VERSION 5.7 ;
  NOWIREEXTENSIONATPIN ON ;
  DIVIDERCHAR "/" ;
  BUSBITCHARS "[]" ;
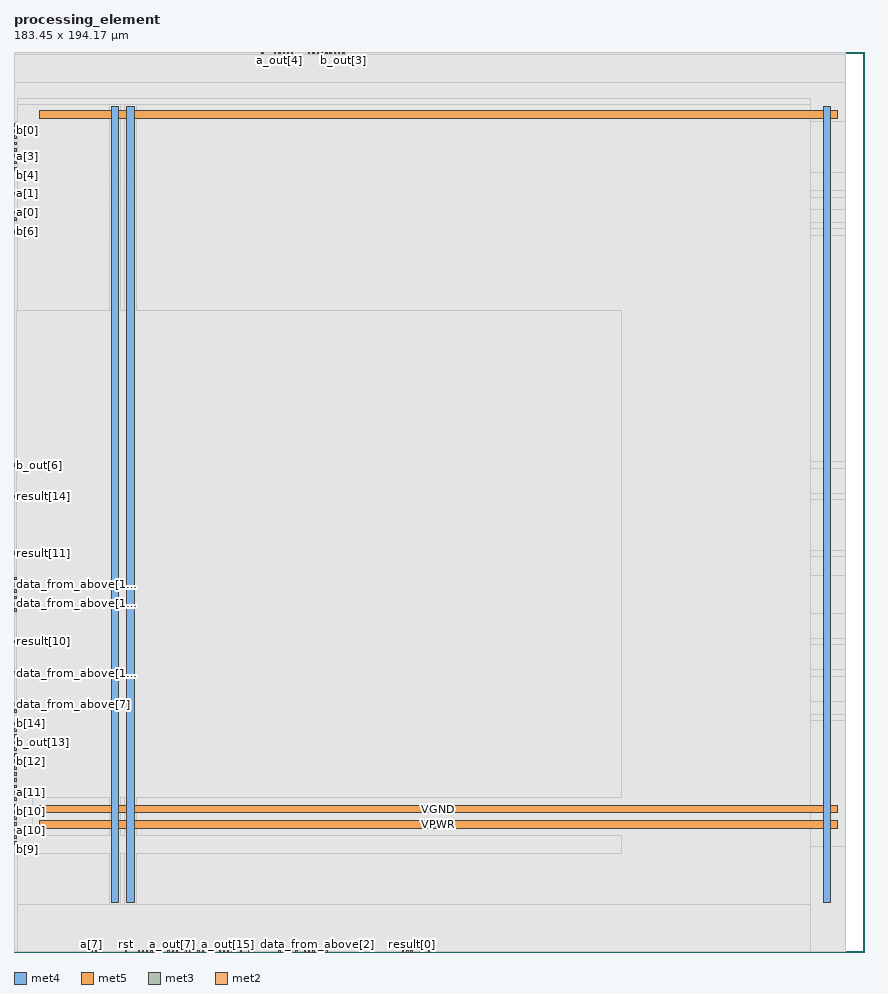
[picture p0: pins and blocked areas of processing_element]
MACRO processing_element
  CLASS BLOCK ;
  FOREIGN processing_element ;
  ORIGIN 0.000 0.000 ;
  SIZE 183.450 BY 194.170 ;
  PIN VGND
    DIRECTION INOUT ;
    USE GROUND ;
    PORT
      LAYER met4 ;
        RECT 24.340 10.640 25.940 182.480 ;
    END
    PORT
      LAYER met5 ;
        RECT 5.520 30.030 177.560 31.630 ;
    END
  END VGND
  PIN VPWR
    DIRECTION INOUT ;
    USE POWER ;
    PORT
      LAYER met4 ;
        RECT 21.040 10.640 22.640 182.480 ;
    END
    PORT
      LAYER met4 ;
        RECT 174.640 10.640 176.240 182.480 ;
    END
    PORT
      LAYER met5 ;
        RECT 5.520 26.730 177.560 28.330 ;
    END
    PORT
      LAYER met5 ;
        RECT 5.520 179.910 177.560 181.510 ;
    END
  END VPWR
  PIN a[0]
    DIRECTION INPUT ;
    USE SIGNAL ;
    ANTENNAGATEAREA 0.196500 ;
    PORT
      LAYER met3 ;
        RECT 0.000 159.160 0.600 159.760 ;
    END
  END a[0]
  PIN a[10]
    DIRECTION INPUT ;
    USE SIGNAL ;
    ANTENNAGATEAREA 0.631200 ;
    ANTENNADIFFAREA 0.434700 ;
    PORT
      LAYER met3 ;
        RECT 0.000 27.240 0.600 27.840 ;
    END
  END a[10]
  PIN a[11]
    DIRECTION INPUT ;
    USE SIGNAL ;
    ANTENNAGATEAREA 0.196500 ;
    PORT
      LAYER met3 ;
        RECT 0.000 34.040 0.600 34.640 ;
    END
  END a[11]
  PIN a[12]
    DIRECTION INPUT ;
    USE SIGNAL ;
    ANTENNAGATEAREA 0.196500 ;
    PORT
      LAYER met3 ;
        RECT 0.000 36.760 0.600 37.360 ;
    END
  END a[12]
  PIN a[13]
    DIRECTION INPUT ;
    USE SIGNAL ;
    ANTENNAGATEAREA 0.196500 ;
    PORT
      LAYER met3 ;
        RECT 0.000 46.280 0.600 46.880 ;
    END
  END a[13]
  PIN a[14]
    DIRECTION INPUT ;
    USE SIGNAL ;
    ANTENNAGATEAREA 0.196500 ;
    PORT
      LAYER met3 ;
        RECT 0.000 35.400 0.600 36.000 ;
    END
  END a[14]
  PIN a[15]
    DIRECTION INPUT ;
    USE SIGNAL ;
    ANTENNAGATEAREA 0.631200 ;
    ANTENNADIFFAREA 0.434700 ;
    PORT
      LAYER met2 ;
        RECT 38.730 0.000 39.010 0.280 ;
    END
  END a[15]
  PIN a[1]
    DIRECTION INPUT ;
    USE SIGNAL ;
    ANTENNAGATEAREA 0.196500 ;
    PORT
      LAYER met3 ;
        RECT 0.000 163.240 0.600 163.840 ;
    END
  END a[1]
  PIN a[2]
    DIRECTION INPUT ;
    USE SIGNAL ;
    ANTENNAGATEAREA 0.196500 ;
    PORT
      LAYER met2 ;
        RECT 59.890 193.890 60.170 194.170 ;
    END
  END a[2]
  PIN a[3]
    DIRECTION INPUT ;
    USE SIGNAL ;
    ANTENNAGATEAREA 0.196500 ;
    PORT
      LAYER met3 ;
        RECT 0.000 171.400 0.600 172.000 ;
    END
  END a[3]
  PIN a[4]
    DIRECTION INPUT ;
    USE SIGNAL ;
    ANTENNAGATEAREA 0.196500 ;
    PORT
      LAYER met3 ;
        RECT 0.000 175.480 0.600 176.080 ;
    END
  END a[4]
  PIN a[5]
    DIRECTION INPUT ;
    USE SIGNAL ;
    ANTENNAGATEAREA 0.196500 ;
    PORT
      LAYER met3 ;
        RECT 0.000 170.040 0.600 170.640 ;
    END
  END a[5]
  PIN a[6]
    DIRECTION INPUT ;
    USE SIGNAL ;
    ANTENNAGATEAREA 0.631200 ;
    ANTENNADIFFAREA 0.434700 ;
    PORT
      LAYER met3 ;
        RECT 0.000 178.200 0.600 178.800 ;
    END
  END a[6]
  PIN a[7]
    DIRECTION INPUT ;
    USE SIGNAL ;
    ANTENNAGATEAREA 0.631200 ;
    ANTENNADIFFAREA 0.434700 ;
    PORT
      LAYER met2 ;
        RECT 16.650 0.000 16.930 0.280 ;
    END
  END a[7]
  PIN a[8]
    DIRECTION INPUT ;
    USE SIGNAL ;
    ANTENNAGATEAREA 0.196500 ;
    PORT
      LAYER met2 ;
        RECT 18.490 0.000 18.770 0.280 ;
    END
  END a[8]
  PIN a[9]
    DIRECTION INPUT ;
    USE SIGNAL ;
    ANTENNAGATEAREA 0.631200 ;
    ANTENNADIFFAREA 0.434700 ;
    PORT
      LAYER met3 ;
        RECT 0.000 24.520 0.600 25.120 ;
    END
  END a[9]
  PIN a_out[0]
    DIRECTION OUTPUT ;
    USE SIGNAL ;
    ANTENNADIFFAREA 0.795200 ;
    PORT
      LAYER met2 ;
        RECT 66.330 193.890 66.610 194.170 ;
    END
  END a_out[0]
  PIN a_out[10]
    DIRECTION OUTPUT ;
    USE SIGNAL ;
    ANTENNADIFFAREA 0.795200 ;
    PORT
      LAYER met2 ;
        RECT 37.810 0.000 38.090 0.280 ;
    END
  END a_out[10]
  PIN a_out[11]
    DIRECTION OUTPUT ;
    USE SIGNAL ;
    ANTENNADIFFAREA 0.795200 ;
    PORT
      LAYER met2 ;
        RECT 40.570 0.000 40.850 0.280 ;
    END
  END a_out[11]
  PIN a_out[12]
    DIRECTION OUTPUT ;
    USE SIGNAL ;
    ANTENNADIFFAREA 0.795200 ;
    PORT
      LAYER met3 ;
        RECT 0.000 38.120 0.600 38.720 ;
    END
  END a_out[12]
  PIN a_out[13]
    DIRECTION OUTPUT ;
    USE SIGNAL ;
    ANTENNADIFFAREA 0.795200 ;
    PORT
      LAYER met2 ;
        RECT 35.050 0.000 35.330 0.280 ;
    END
  END a_out[13]
  PIN a_out[14]
    DIRECTION OUTPUT ;
    USE SIGNAL ;
    ANTENNADIFFAREA 0.795200 ;
    PORT
      LAYER met2 ;
        RECT 35.970 0.000 36.250 0.280 ;
    END
  END a_out[14]
  PIN a_out[15]
    DIRECTION OUTPUT ;
    USE SIGNAL ;
    ANTENNADIFFAREA 0.795200 ;
    PORT
      LAYER met2 ;
        RECT 46.090 0.000 46.370 0.280 ;
    END
  END a_out[15]
  PIN a_out[1]
    DIRECTION OUTPUT ;
    USE SIGNAL ;
    ANTENNADIFFAREA 0.795200 ;
    PORT
      LAYER met2 ;
        RECT 67.250 193.890 67.530 194.170 ;
    END
  END a_out[1]
  PIN a_out[2]
    DIRECTION OUTPUT ;
    USE SIGNAL ;
    ANTENNADIFFAREA 0.795200 ;
    PORT
      LAYER met2 ;
        RECT 70.010 193.890 70.290 194.170 ;
    END
  END a_out[2]
  PIN a_out[3]
    DIRECTION OUTPUT ;
    USE SIGNAL ;
    ANTENNADIFFAREA 0.795200 ;
    PORT
      LAYER met2 ;
        RECT 63.570 193.890 63.850 194.170 ;
    END
  END a_out[3]
  PIN a_out[4]
    DIRECTION OUTPUT ;
    USE SIGNAL ;
    ANTENNADIFFAREA 0.795200 ;
    PORT
      LAYER met2 ;
        RECT 57.130 193.890 57.410 194.170 ;
    END
  END a_out[4]
  PIN a_out[5]
    DIRECTION OUTPUT ;
    USE SIGNAL ;
    ANTENNADIFFAREA 0.795200 ;
    PORT
      LAYER met2 ;
        RECT 58.050 193.890 58.330 194.170 ;
    END
  END a_out[5]
  PIN a_out[6]
    DIRECTION OUTPUT ;
    USE SIGNAL ;
    ANTENNADIFFAREA 0.795200 ;
    PORT
      LAYER met2 ;
        RECT 53.450 193.890 53.730 194.170 ;
    END
  END a_out[6]
  PIN a_out[7]
    DIRECTION OUTPUT ;
    USE SIGNAL ;
    ANTENNADIFFAREA 0.795200 ;
    PORT
      LAYER met2 ;
        RECT 34.130 0.000 34.410 0.280 ;
    END
  END a_out[7]
  PIN a_out[8]
    DIRECTION OUTPUT ;
    USE SIGNAL ;
    ANTENNADIFFAREA 0.795200 ;
    PORT
      LAYER met2 ;
        RECT 33.210 0.000 33.490 0.280 ;
    END
  END a_out[8]
  PIN a_out[9]
    DIRECTION OUTPUT ;
    USE SIGNAL ;
    ANTENNADIFFAREA 0.795200 ;
    PORT
      LAYER met2 ;
        RECT 36.890 0.000 37.170 0.280 ;
    END
  END a_out[9]
  PIN b[0]
    DIRECTION INPUT ;
    USE SIGNAL ;
    ANTENNAGATEAREA 0.196500 ;
    PORT
      LAYER met3 ;
        RECT 0.000 176.840 0.600 177.440 ;
    END
  END b[0]
  PIN b[10]
    DIRECTION INPUT ;
    USE SIGNAL ;
    ANTENNAGATEAREA 0.631200 ;
    ANTENNADIFFAREA 0.434700 ;
    PORT
      LAYER met3 ;
        RECT 0.000 29.960 0.600 30.560 ;
    END
  END b[10]
  PIN b[11]
    DIRECTION INPUT ;
    USE SIGNAL ;
    ANTENNAGATEAREA 0.631200 ;
    ANTENNADIFFAREA 0.434700 ;
    PORT
      LAYER met3 ;
        RECT 0.000 32.680 0.600 33.280 ;
    END
  END b[11]
  PIN b[12]
    DIRECTION INPUT ;
    USE SIGNAL ;
    ANTENNAGATEAREA 0.196500 ;
    PORT
      LAYER met3 ;
        RECT 0.000 40.840 0.600 41.440 ;
    END
  END b[12]
  PIN b[13]
    DIRECTION INPUT ;
    USE SIGNAL ;
    ANTENNAGATEAREA 0.196500 ;
    PORT
      LAYER met3 ;
        RECT 0.000 42.200 0.600 42.800 ;
    END
  END b[13]
  PIN b[14]
    DIRECTION INPUT ;
    USE SIGNAL ;
    ANTENNAGATEAREA 0.631200 ;
    ANTENNADIFFAREA 0.434700 ;
    PORT
      LAYER met3 ;
        RECT 0.000 47.640 0.600 48.240 ;
    END
  END b[14]
  PIN b[15]
    DIRECTION INPUT ;
    USE SIGNAL ;
    ANTENNAGATEAREA 0.196500 ;
    PORT
      LAYER met2 ;
        RECT 39.650 0.000 39.930 0.280 ;
    END
  END b[15]
  PIN b[1]
    DIRECTION INPUT ;
    USE SIGNAL ;
    ANTENNAGATEAREA 0.196500 ;
    PORT
      LAYER met2 ;
        RECT 56.210 193.890 56.490 194.170 ;
    END
  END b[1]
  PIN b[2]
    DIRECTION INPUT ;
    USE SIGNAL ;
    ANTENNAGATEAREA 0.196500 ;
    PORT
      LAYER met3 ;
        RECT 0.000 174.120 0.600 174.720 ;
    END
  END b[2]
  PIN b[3]
    DIRECTION INPUT ;
    USE SIGNAL ;
    ANTENNAGATEAREA 0.196500 ;
    PORT
      LAYER met3 ;
        RECT 0.000 172.760 0.600 173.360 ;
    END
  END b[3]
  PIN b[4]
    DIRECTION INPUT ;
    USE SIGNAL ;
    ANTENNAGATEAREA 0.631200 ;
    ANTENNADIFFAREA 0.434700 ;
    PORT
      LAYER met3 ;
        RECT 0.000 168.680 0.600 169.280 ;
    END
  END b[4]
  PIN b[5]
    DIRECTION INPUT ;
    USE SIGNAL ;
    ANTENNAGATEAREA 0.196500 ;
    PORT
      LAYER met3 ;
        RECT 0.000 157.800 0.600 158.400 ;
    END
  END b[5]
  PIN b[6]
    DIRECTION INPUT ;
    USE SIGNAL ;
    ANTENNAGATEAREA 0.196500 ;
    PORT
      LAYER met3 ;
        RECT 0.000 155.080 0.600 155.680 ;
    END
  END b[6]
  PIN b[7]
    DIRECTION INPUT ;
    USE SIGNAL ;
    ANTENNAGATEAREA 0.631200 ;
    ANTENNADIFFAREA 0.434700 ;
    PORT
      LAYER met3 ;
        RECT 0.000 28.600 0.600 29.200 ;
    END
  END b[7]
  PIN b[8]
    DIRECTION INPUT ;
    USE SIGNAL ;
    ANTENNAGATEAREA 0.631200 ;
    ANTENNADIFFAREA 0.434700 ;
    PORT
      LAYER met3 ;
        RECT 0.000 25.880 0.600 26.480 ;
    END
  END b[8]
  PIN b[9]
    DIRECTION INPUT ;
    USE SIGNAL ;
    ANTENNAGATEAREA 0.196500 ;
    PORT
      LAYER met3 ;
        RECT 0.000 23.160 0.600 23.760 ;
    END
  END b[9]
  PIN b_out[0]
    DIRECTION OUTPUT ;
    USE SIGNAL ;
    ANTENNADIFFAREA 0.795200 ;
    PORT
      LAYER met2 ;
        RECT 58.970 193.890 59.250 194.170 ;
    END
  END b_out[0]
  PIN b_out[10]
    DIRECTION OUTPUT ;
    USE SIGNAL ;
    ANTENNADIFFAREA 0.795200 ;
    PORT
      LAYER met2 ;
        RECT 26.770 0.000 27.050 0.280 ;
    END
  END b_out[10]
  PIN b_out[11]
    DIRECTION OUTPUT ;
    USE SIGNAL ;
    ANTENNADIFFAREA 0.795200 ;
    PORT
      LAYER met3 ;
        RECT 0.000 31.320 0.600 31.920 ;
    END
  END b_out[11]
  PIN b_out[12]
    DIRECTION OUTPUT ;
    USE SIGNAL ;
    ANTENNADIFFAREA 0.795200 ;
    PORT
      LAYER met3 ;
        RECT 0.000 39.480 0.600 40.080 ;
    END
  END b_out[12]
  PIN b_out[13]
    DIRECTION OUTPUT ;
    USE SIGNAL ;
    ANTENNADIFFAREA 0.795200 ;
    PORT
      LAYER met3 ;
        RECT 0.000 43.560 0.600 44.160 ;
    END
  END b_out[13]
  PIN b_out[14]
    DIRECTION OUTPUT ;
    USE SIGNAL ;
    ANTENNADIFFAREA 0.795200 ;
    PORT
      LAYER met3 ;
        RECT 0.000 49.000 0.600 49.600 ;
    END
  END b_out[14]
  PIN b_out[15]
    DIRECTION OUTPUT ;
    USE SIGNAL ;
    ANTENNADIFFAREA 0.795200 ;
    PORT
      LAYER met2 ;
        RECT 47.010 0.000 47.290 0.280 ;
    END
  END b_out[15]
  PIN b_out[1]
    DIRECTION OUTPUT ;
    USE SIGNAL ;
    ANTENNADIFFAREA 0.795200 ;
    PORT
      LAYER met2 ;
        RECT 65.410 193.890 65.690 194.170 ;
    END
  END b_out[1]
  PIN b_out[2]
    DIRECTION OUTPUT ;
    USE SIGNAL ;
    ANTENNADIFFAREA 0.795200 ;
    PORT
      LAYER met2 ;
        RECT 68.170 193.890 68.450 194.170 ;
    END
  END b_out[2]
  PIN b_out[3]
    DIRECTION OUTPUT ;
    USE SIGNAL ;
    ANTENNADIFFAREA 0.795200 ;
    PORT
      LAYER met2 ;
        RECT 70.930 193.890 71.210 194.170 ;
    END
  END b_out[3]
  PIN b_out[4]
    DIRECTION OUTPUT ;
    USE SIGNAL ;
    ANTENNADIFFAREA 0.795200 ;
    PORT
      LAYER met2 ;
        RECT 69.090 193.890 69.370 194.170 ;
    END
  END b_out[4]
  PIN b_out[5]
    DIRECTION OUTPUT ;
    USE SIGNAL ;
    ANTENNADIFFAREA 0.795200 ;
    PORT
      LAYER met2 ;
        RECT 64.490 193.890 64.770 194.170 ;
    END
  END b_out[5]
  PIN b_out[6]
    DIRECTION OUTPUT ;
    USE SIGNAL ;
    ANTENNADIFFAREA 0.795200 ;
    PORT
      LAYER met3 ;
        RECT 0.000 104.760 0.600 105.360 ;
    END
  END b_out[6]
  PIN b_out[7]
    DIRECTION OUTPUT ;
    USE SIGNAL ;
    ANTENNADIFFAREA 0.795200 ;
    PORT
      LAYER met2 ;
        RECT 27.690 0.000 27.970 0.280 ;
    END
  END b_out[7]
  PIN b_out[8]
    DIRECTION OUTPUT ;
    USE SIGNAL ;
    ANTENNADIFFAREA 0.795200 ;
    PORT
      LAYER met2 ;
        RECT 28.610 0.000 28.890 0.280 ;
    END
  END b_out[8]
  PIN b_out[9]
    DIRECTION OUTPUT ;
    USE SIGNAL ;
    ANTENNADIFFAREA 0.795200 ;
    PORT
      LAYER met2 ;
        RECT 29.530 0.000 29.810 0.280 ;
    END
  END b_out[9]
  PIN clear
    DIRECTION INPUT ;
    USE SIGNAL ;
    ANTENNAGATEAREA 0.196500 ;
    PORT
      LAYER met2 ;
        RECT 51.610 0.000 51.890 0.280 ;
    END
  END clear
  PIN clk
    DIRECTION INPUT ;
    USE SIGNAL ;
    ANTENNAGATEAREA 0.852000 ;
    PORT
      LAYER met2 ;
        RECT 17.570 0.000 17.850 0.280 ;
    END
  END clk
  PIN data_from_above[0]
    DIRECTION INPUT ;
    USE SIGNAL ;
    ANTENNAGATEAREA 0.196500 ;
    PORT
      LAYER met2 ;
        RECT 63.570 0.000 63.850 0.280 ;
    END
  END data_from_above[0]
  PIN data_from_above[10]
    DIRECTION INPUT ;
    USE SIGNAL ;
    ANTENNAGATEAREA 0.196500 ;
    PORT
      LAYER met3 ;
        RECT 0.000 59.880 0.600 60.480 ;
    END
  END data_from_above[10]
  PIN data_from_above[11]
    DIRECTION INPUT ;
    USE SIGNAL ;
    ANTENNAGATEAREA 0.196500 ;
    PORT
      LAYER met3 ;
        RECT 0.000 78.920 0.600 79.520 ;
    END
  END data_from_above[11]
  PIN data_from_above[12]
    DIRECTION INPUT ;
    USE SIGNAL ;
    ANTENNAGATEAREA 0.196500 ;
    PORT
      LAYER met3 ;
        RECT 0.000 74.840 0.600 75.440 ;
    END
  END data_from_above[12]
  PIN data_from_above[13]
    DIRECTION INPUT ;
    USE SIGNAL ;
    ANTENNAGATEAREA 0.196500 ;
    PORT
      LAYER met3 ;
        RECT 0.000 77.560 0.600 78.160 ;
    END
  END data_from_above[13]
  PIN data_from_above[14]
    DIRECTION INPUT ;
    USE SIGNAL ;
    ANTENNAGATEAREA 0.196500 ;
    PORT
      LAYER met3 ;
        RECT 0.000 80.280 0.600 80.880 ;
    END
  END data_from_above[14]
  PIN data_from_above[15]
    DIRECTION INPUT ;
    USE SIGNAL ;
    ANTENNAGATEAREA 0.196500 ;
    PORT
      LAYER met2 ;
        RECT 57.130 0.000 57.410 0.280 ;
    END
  END data_from_above[15]
  PIN data_from_above[1]
    DIRECTION INPUT ;
    USE SIGNAL ;
    ANTENNAGATEAREA 0.196500 ;
    PORT
      LAYER met2 ;
        RECT 62.650 0.000 62.930 0.280 ;
    END
  END data_from_above[1]
  PIN data_from_above[2]
    DIRECTION INPUT ;
    USE SIGNAL ;
    ANTENNAGATEAREA 0.196500 ;
    PORT
      LAYER met2 ;
        RECT 65.410 0.000 65.690 0.280 ;
    END
  END data_from_above[2]
  PIN data_from_above[3]
    DIRECTION INPUT ;
    USE SIGNAL ;
    ANTENNAGATEAREA 0.196500 ;
    PORT
      LAYER met2 ;
        RECT 67.250 0.000 67.530 0.280 ;
    END
  END data_from_above[3]
  PIN data_from_above[4]
    DIRECTION INPUT ;
    USE SIGNAL ;
    ANTENNAGATEAREA 0.196500 ;
    PORT
      LAYER met2 ;
        RECT 64.490 0.000 64.770 0.280 ;
    END
  END data_from_above[4]
  PIN data_from_above[5]
    DIRECTION INPUT ;
    USE SIGNAL ;
    ANTENNAGATEAREA 0.196500 ;
    PORT
      LAYER met2 ;
        RECT 66.330 0.000 66.610 0.280 ;
    END
  END data_from_above[5]
  PIN data_from_above[6]
    DIRECTION INPUT ;
    USE SIGNAL ;
    ANTENNAGATEAREA 0.196500 ;
    PORT
      LAYER met2 ;
        RECT 48.850 0.000 49.130 0.280 ;
    END
  END data_from_above[6]
  PIN data_from_above[7]
    DIRECTION INPUT ;
    USE SIGNAL ;
    ANTENNAGATEAREA 0.196500 ;
    PORT
      LAYER met3 ;
        RECT 0.000 53.080 0.600 53.680 ;
    END
  END data_from_above[7]
  PIN data_from_above[8]
    DIRECTION INPUT ;
    USE SIGNAL ;
    ANTENNAGATEAREA 0.196500 ;
    PORT
      LAYER met2 ;
        RECT 42.410 0.000 42.690 0.280 ;
    END
  END data_from_above[8]
  PIN data_from_above[9]
    DIRECTION INPUT ;
    USE SIGNAL ;
    ANTENNAGATEAREA 0.631200 ;
    ANTENNADIFFAREA 0.434700 ;
    PORT
      LAYER met2 ;
        RECT 41.490 0.000 41.770 0.280 ;
    END
  END data_from_above[9]
  PIN drain_en
    DIRECTION INPUT ;
    USE SIGNAL ;
    ANTENNAGATEAREA 0.631200 ;
    ANTENNADIFFAREA 0.434700 ;
    PORT
      LAYER met2 ;
        RECT 50.690 0.000 50.970 0.280 ;
    END
  END drain_en
  PIN en
    DIRECTION INPUT ;
    USE SIGNAL ;
    ANTENNAGATEAREA 0.631200 ;
    ANTENNADIFFAREA 0.434700 ;
    PORT
      LAYER met3 ;
        RECT 0.000 44.920 0.600 45.520 ;
    END
  END en
  PIN result[0]
    DIRECTION OUTPUT ;
    USE SIGNAL ;
    ANTENNADIFFAREA 0.795200 ;
    PORT
      LAYER met2 ;
        RECT 85.650 0.000 85.930 0.280 ;
    END
  END result[0]
  PIN result[10]
    DIRECTION OUTPUT ;
    USE SIGNAL ;
    ANTENNADIFFAREA 0.795200 ;
    PORT
      LAYER met3 ;
        RECT 0.000 66.680 0.600 67.280 ;
    END
  END result[10]
  PIN result[11]
    DIRECTION OUTPUT ;
    USE SIGNAL ;
    ANTENNADIFFAREA 0.795200 ;
    PORT
      LAYER met3 ;
        RECT 0.000 85.720 0.600 86.320 ;
    END
  END result[11]
  PIN result[12]
    DIRECTION OUTPUT ;
    USE SIGNAL ;
    ANTENNADIFFAREA 0.795200 ;
    PORT
      LAYER met3 ;
        RECT 0.000 73.480 0.600 74.080 ;
    END
  END result[12]
  PIN result[13]
    DIRECTION OUTPUT ;
    USE SIGNAL ;
    ANTENNADIFFAREA 0.795200 ;
    PORT
      LAYER met3 ;
        RECT 0.000 76.200 0.600 76.800 ;
    END
  END result[13]
  PIN result[14]
    DIRECTION OUTPUT ;
    USE SIGNAL ;
    ANTENNADIFFAREA 0.795200 ;
    PORT
      LAYER met3 ;
        RECT 0.000 97.960 0.600 98.560 ;
    END
  END result[14]
  PIN result[15]
    DIRECTION OUTPUT ;
    USE SIGNAL ;
    ANTENNADIFFAREA 0.795200 ;
    PORT
      LAYER met2 ;
        RECT 59.890 0.000 60.170 0.280 ;
    END
  END result[15]
  PIN result[1]
    DIRECTION OUTPUT ;
    USE SIGNAL ;
    ANTENNADIFFAREA 0.795200 ;
    PORT
      LAYER met2 ;
        RECT 87.490 0.000 87.770 0.280 ;
    END
  END result[1]
  PIN result[2]
    DIRECTION OUTPUT ;
    USE SIGNAL ;
    ANTENNADIFFAREA 0.795200 ;
    PORT
      LAYER met2 ;
        RECT 84.730 0.000 85.010 0.280 ;
    END
  END result[2]
  PIN result[3]
    DIRECTION OUTPUT ;
    USE SIGNAL ;
    ANTENNADIFFAREA 0.795200 ;
    PORT
      LAYER met2 ;
        RECT 89.330 0.000 89.610 0.280 ;
    END
  END result[3]
  PIN result[4]
    DIRECTION OUTPUT ;
    USE SIGNAL ;
    ANTENNADIFFAREA 0.795200 ;
    PORT
      LAYER met2 ;
        RECT 60.810 0.000 61.090 0.280 ;
    END
  END result[4]
  PIN result[5]
    DIRECTION OUTPUT ;
    USE SIGNAL ;
    ANTENNADIFFAREA 0.795200 ;
    PORT
      LAYER met2 ;
        RECT 83.810 0.000 84.090 0.280 ;
    END
  END result[5]
  PIN result[6]
    DIRECTION OUTPUT ;
    USE SIGNAL ;
    ANTENNADIFFAREA 0.795200 ;
    PORT
      LAYER met2 ;
        RECT 58.970 0.000 59.250 0.280 ;
    END
  END result[6]
  PIN result[7]
    DIRECTION OUTPUT ;
    USE SIGNAL ;
    ANTENNADIFFAREA 0.795200 ;
    PORT
      LAYER met3 ;
        RECT 0.000 51.720 0.600 52.320 ;
    END
  END result[7]
  PIN result[8]
    DIRECTION OUTPUT ;
    USE SIGNAL ;
    ANTENNADIFFAREA 0.795200 ;
    PORT
      LAYER met2 ;
        RECT 45.170 0.000 45.450 0.280 ;
    END
  END result[8]
  PIN result[9]
    DIRECTION OUTPUT ;
    USE SIGNAL ;
    ANTENNADIFFAREA 0.795200 ;
    PORT
      LAYER met2 ;
        RECT 44.250 0.000 44.530 0.280 ;
    END
  END result[9]
  PIN rst
    DIRECTION INPUT ;
    USE SIGNAL ;
    ANTENNAGATEAREA 0.196500 ;
    PORT
      LAYER met2 ;
        RECT 24.010 0.000 24.290 0.280 ;
    END
  END rst
  OBS
      LAYER nwell ;
        RECT 5.330 10.795 177.750 182.430 ;
      LAYER li1 ;
        RECT 5.520 10.795 177.560 182.325 ;
      LAYER met1 ;
        RECT 0.530 0.380 179.330 194.100 ;
      LAYER met2 ;
        RECT 0.090 193.610 53.170 194.130 ;
        RECT 54.010 193.610 55.930 194.130 ;
        RECT 56.770 193.610 56.850 194.130 ;
        RECT 57.690 193.610 57.770 194.130 ;
        RECT 58.610 193.610 58.690 194.130 ;
        RECT 59.530 193.610 59.610 194.130 ;
        RECT 60.450 193.610 63.290 194.130 ;
        RECT 64.130 193.610 64.210 194.130 ;
        RECT 65.050 193.610 65.130 194.130 ;
        RECT 65.970 193.610 66.050 194.130 ;
        RECT 66.890 193.610 66.970 194.130 ;
        RECT 67.810 193.610 67.890 194.130 ;
        RECT 68.730 193.610 68.810 194.130 ;
        RECT 69.650 193.610 69.730 194.130 ;
        RECT 70.570 193.610 70.650 194.130 ;
        RECT 71.490 193.610 179.310 194.130 ;
        RECT 0.090 0.560 179.310 193.610 ;
        RECT 0.090 0.155 16.370 0.560 ;
        RECT 17.210 0.155 17.290 0.560 ;
        RECT 18.130 0.155 18.210 0.560 ;
        RECT 19.050 0.155 23.730 0.560 ;
        RECT 24.570 0.155 26.490 0.560 ;
        RECT 27.330 0.155 27.410 0.560 ;
        RECT 28.250 0.155 28.330 0.560 ;
        RECT 29.170 0.155 29.250 0.560 ;
        RECT 30.090 0.155 32.930 0.560 ;
        RECT 33.770 0.155 33.850 0.560 ;
        RECT 34.690 0.155 34.770 0.560 ;
        RECT 35.610 0.155 35.690 0.560 ;
        RECT 36.530 0.155 36.610 0.560 ;
        RECT 37.450 0.155 37.530 0.560 ;
        RECT 38.370 0.155 38.450 0.560 ;
        RECT 39.290 0.155 39.370 0.560 ;
        RECT 40.210 0.155 40.290 0.560 ;
        RECT 41.130 0.155 41.210 0.560 ;
        RECT 42.050 0.155 42.130 0.560 ;
        RECT 42.970 0.155 43.970 0.560 ;
        RECT 44.810 0.155 44.890 0.560 ;
        RECT 45.730 0.155 45.810 0.560 ;
        RECT 46.650 0.155 46.730 0.560 ;
        RECT 47.570 0.155 48.570 0.560 ;
        RECT 49.410 0.155 50.410 0.560 ;
        RECT 51.250 0.155 51.330 0.560 ;
        RECT 52.170 0.155 56.850 0.560 ;
        RECT 57.690 0.155 58.690 0.560 ;
        RECT 59.530 0.155 59.610 0.560 ;
        RECT 60.450 0.155 60.530 0.560 ;
        RECT 61.370 0.155 62.370 0.560 ;
        RECT 63.210 0.155 63.290 0.560 ;
        RECT 64.130 0.155 64.210 0.560 ;
        RECT 65.050 0.155 65.130 0.560 ;
        RECT 65.970 0.155 66.050 0.560 ;
        RECT 66.890 0.155 66.970 0.560 ;
        RECT 67.810 0.155 83.530 0.560 ;
        RECT 84.370 0.155 84.450 0.560 ;
        RECT 85.290 0.155 85.370 0.560 ;
        RECT 86.210 0.155 87.210 0.560 ;
        RECT 88.050 0.155 89.050 0.560 ;
        RECT 89.890 0.155 179.310 0.560 ;
      LAYER met3 ;
        RECT 0.065 179.200 179.335 187.505 ;
        RECT 1.000 168.280 179.335 179.200 ;
        RECT 0.065 164.240 179.335 168.280 ;
        RECT 1.000 162.840 179.335 164.240 ;
        RECT 0.065 160.160 179.335 162.840 ;
        RECT 1.000 157.400 179.335 160.160 ;
        RECT 0.065 156.080 179.335 157.400 ;
        RECT 1.000 154.680 179.335 156.080 ;
        RECT 0.065 105.760 179.335 154.680 ;
        RECT 1.000 104.360 179.335 105.760 ;
        RECT 0.065 98.960 179.335 104.360 ;
        RECT 1.000 97.560 179.335 98.960 ;
        RECT 0.065 86.720 179.335 97.560 ;
        RECT 1.000 85.320 179.335 86.720 ;
        RECT 0.065 81.280 179.335 85.320 ;
        RECT 1.000 73.080 179.335 81.280 ;
        RECT 0.065 67.680 179.335 73.080 ;
        RECT 1.000 66.280 179.335 67.680 ;
        RECT 0.065 60.880 179.335 66.280 ;
        RECT 1.000 59.480 179.335 60.880 ;
        RECT 0.065 54.080 179.335 59.480 ;
        RECT 1.000 51.320 179.335 54.080 ;
        RECT 0.065 50.000 179.335 51.320 ;
        RECT 1.000 22.760 179.335 50.000 ;
        RECT 0.065 0.175 179.335 22.760 ;
      LAYER met4 ;
        RECT 0.790 182.880 171.745 184.105 ;
        RECT 0.790 10.240 20.640 182.880 ;
        RECT 23.040 10.240 23.940 182.880 ;
        RECT 26.340 10.240 171.745 182.880 ;
        RECT 0.790 0.175 171.745 10.240 ;
      LAYER met5 ;
        RECT 0.580 33.230 130.980 138.500 ;
        RECT 0.580 25.130 3.920 33.230 ;
        RECT 0.580 21.300 130.980 25.130 ;
  END
END processing_element
END LIBRARY

